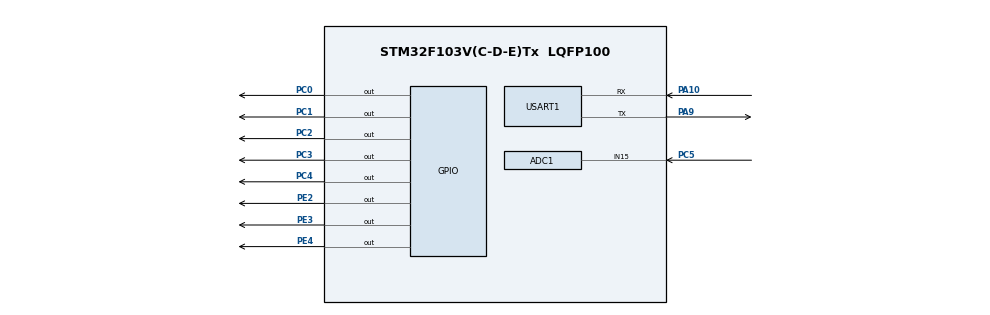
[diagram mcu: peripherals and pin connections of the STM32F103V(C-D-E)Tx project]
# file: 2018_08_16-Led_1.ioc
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ADC1.Channel-0\#ChannelRegularConversion=ADC_CHANNEL_15
ADC1.ContinuousConvMode=DISABLE
ADC1.DataAlign=ADC_DATAALIGN_RIGHT
ADC1.DiscontinuousConvMode=DISABLE
ADC1.EnableAnalogWatchDog=false
ADC1.EnableRegularConversion=ENABLE
ADC1.ExternalTrigConv=ADC_SOFTWARE_START
ADC1.InjNumberOfConversion=0
ADC1.NbrOfConversion=1
ADC1.NbrOfConversionFlag=1
ADC1.Rank-0\#ChannelRegularConversion=1
ADC1.SamplingTime-0\#ChannelRegularConversion=ADC_SAMPLETIME_1CYCLE_5
ADC1.ScanConvMode=ADC_SCAN_DISABLE
ADC1.master=1
Mcu.Family=STM32F1
Mcu.Name=STM32F103V(C-D-E)Tx
Mcu.Package=LQFP100
NVIC.PriorityGroup=NVIC_PRIORITYGROUP_4
OSC_IN.Mode=HSE-External-Oscillator
OSC_IN.Signal=RCC_OSC_IN
OSC_OUT.Mode=HSE-External-Oscillator
OSC_OUT.Signal=RCC_OSC_OUT
PA10.Mode=Asynchronous
PA10.Signal=USART1_RX
PA9.Mode=Asynchronous
PA9.Signal=USART1_TX
PC0.Signal=GPIO_Output
PC1.Signal=GPIO_Output
PC2.Signal=GPIO_Output
PC3.Signal=GPIO_Output
PC4.Signal=GPIO_Output
PC5.Signal=ADCx_IN15
PC6.Signal=S_TIM3_CH1
PE2.Signal=GPIO_Output
PE3.Signal=GPIO_Output
PE4.Signal=GPIO_Output
ProjectManager.HeapSize=0x200
ProjectManager.StackSize=0x400
ProjectManager.TargetToolchain=EWARM
RCC.ADCPresc=RCC_ADCPCLK2_DIV4
RCC.AHBFreq_Value=56000000
RCC.APB1CLKDivider=RCC_HCLK_DIV2
RCC.APB1Freq_Value=28000000
RCC.APB1TimFreq_Value=56000000
RCC.APB2Freq_Value=56000000
RCC.APB2TimFreq_Value=56000000
RCC.HCLKFreq_Value=56000000
RCC.PLLMUL=RCC_PLL_MUL7
RCC.PLLSourceVirtual=RCC_PLLSOURCE_HSE
RCC.SYSCLKFreq_VALUE=56000000
RCC.SYSCLKSource=RCC_SYSCLKSOURCE_PLLCLK
RCC.USBFreq_Value=56000000
SH.ADCx_IN15.0=ADC1_IN15,IN15
SH.S_TIM3_CH1.0=TIM3_CH1
USART1.VirtualMode=VM_ASYNC
VP_SYS_VS_ND.Mode=No_Debug
board=custom

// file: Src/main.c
/**
  ******************************************************************************
  * @file           : main.c
  * @brief          : Main program body
  ******************************************************************************
  ** This notice applies to any and all portions of this file
  * that are not between comment pairs USER CODE BEGIN and
  * USER CODE END. Other portions of this file, whether
  * inserted by the user or by software development tools
  * are owned by their respective copyright owners.
  *
  * COPYRIGHT(c) 2018 STMicroelectronics
  *
  * Redistribution and use in source and binary forms, with or without modification,
  * are permitted provided that the following conditions are met:
  *   1. Redistributions of source code must retain the above copyright notice,
  *      this list of conditions and the following disclaimer.
  *   2. Redistributions in binary form must reproduce the above copyright notice,
  *      this list of conditions and the following disclaimer in the documentation
  *      and/or other materials provided with the distribution.
  *   3. Neither the name of STMicroelectronics nor the names of its contributors
  *      may be used to endorse or promote products derived from this software
  *      without specific prior written permission.
  *
  * THIS SOFTWARE IS PROVIDED BY THE COPYRIGHT HOLDERS AND CONTRIBUTORS "AS IS"
  * AND ANY EXPRESS OR IMPLIED WARRANTIES, INCLUDING, BUT NOT LIMITED TO, THE
  * IMPLIED WARRANTIES OF MERCHANTABILITY AND FITNESS FOR A PARTICULAR PURPOSE ARE
  * DISCLAIMED. IN NO EVENT SHALL THE COPYRIGHT HOLDER OR CONTRIBUTORS BE LIABLE
  * FOR ANY DIRECT, INDIRECT, INCIDENTAL, SPECIAL, EXEMPLARY, OR CONSEQUENTIAL
  * DAMAGES (INCLUDING, BUT NOT LIMITED TO, PROCUREMENT OF SUBSTITUTE GOODS OR
  * SERVICES; LOSS OF USE, DATA, OR PROFITS; OR BUSINESS INTERRUPTION) HOWEVER
  * CAUSED AND ON ANY THEORY OF LIABILITY, WHETHER IN CONTRACT, STRICT LIABILITY,
  * OR TORT (INCLUDING NEGLIGENCE OR OTHERWISE) ARISING IN ANY WAY OUT OF THE USE
  * OF THIS SOFTWARE, EVEN IF ADVISED OF THE POSSIBILITY OF SUCH DAMAGE.
  *
  ******************************************************************************
  */
#include "main.h"
#include "stm32f1xx_hal.h"
#include "adc.h"
#include "usart.h"
#include "gpio.h"

/* USER CODE BEGIN PV */
/* Private variables ---------------------------------------------------------*/

/* USER CODE END PV */

void SystemClock_Config(void);

/* USER CODE BEGIN PFP */
/* Private function prototypes -----------------------------------------------*/

/* USER CODE END PFP */

int main(void)
{

  /* MCU Configuration----------------------------------------------------------*/

  /* Reset of all peripherals, Initializes the Flash interface and the Systick. */
  HAL_Init();

  /* Configure the system clock */
  SystemClock_Config();

  /* Initialize all configured peripherals */
  MX_GPIO_Init();
  MX_ADC1_Init();
  MX_USART1_UART_Init();

  /* Infinite loop */
  /* USER CODE BEGIN WHILE */
  while (1)
  {
    if(!(HAL_GPIO_ReadPin(GPIOC, GPIO_PIN_0)) )
    {
      HAL_GPIO_WritePin(GPIOE, GPIO_PIN_2|GPIO_PIN_3|GPIO_PIN_4, GPIO_PIN_SET);
    }
    else{
      HAL_GPIO_WritePin(GPIOE, GPIO_PIN_2|GPIO_PIN_3|GPIO_PIN_4, GPIO_PIN_RESET);
    }

  /* USER CODE END WHILE */

  }

}

void SystemClock_Config(void)
{

  RCC_OscInitTypeDef RCC_OscInitStruct;
  RCC_ClkInitTypeDef RCC_ClkInitStruct;
  RCC_PeriphCLKInitTypeDef PeriphClkInit;

    /**Initializes the CPU, AHB and APB busses clocks
    */
  RCC_OscInitStruct.OscillatorType = RCC_OSCILLATORTYPE_HSE;
  RCC_OscInitStruct.HSEState = RCC_HSE_ON;
  RCC_OscInitStruct.HSEPredivValue = RCC_HSE_PREDIV_DIV1;
  RCC_OscInitStruct.HSIState = RCC_HSI_ON;
  RCC_OscInitStruct.PLL.PLLState = RCC_PLL_ON;
  RCC_OscInitStruct.PLL.PLLSource = RCC_PLLSOURCE_HSE;
  RCC_OscInitStruct.PLL.PLLMUL = RCC_PLL_MUL9;
  if (HAL_RCC_OscConfig(&RCC_OscInitStruct) != HAL_OK)
  {
    _Error_Handler(__FILE__, __LINE__);
  }

    /**Initializes the CPU, AHB and APB busses clocks
    */
  RCC_ClkInitStruct.ClockType = RCC_CLOCKTYPE_HCLK|RCC_CLOCKTYPE_SYSCLK
                              |RCC_CLOCKTYPE_PCLK1|RCC_CLOCKTYPE_PCLK2;
  RCC_ClkInitStruct.SYSCLKSource = RCC_SYSCLKSOURCE_PLLCLK;
  RCC_ClkInitStruct.AHBCLKDivider = RCC_SYSCLK_DIV1;
  RCC_ClkInitStruct.APB1CLKDivider = RCC_HCLK_DIV2;
  RCC_ClkInitStruct.APB2CLKDivider = RCC_HCLK_DIV1;

  if (HAL_RCC_ClockConfig(&RCC_ClkInitStruct, FLASH_LATENCY_2) != HAL_OK)
  {
    _Error_Handler(__FILE__, __LINE__);
  }

  PeriphClkInit.PeriphClockSelection = RCC_PERIPHCLK_ADC;
  PeriphClkInit.AdcClockSelection = RCC_ADCPCLK2_DIV2;
  if (HAL_RCCEx_PeriphCLKConfig(&PeriphClkInit) != HAL_OK)
  {
    _Error_Handler(__FILE__, __LINE__);
  }

    /**Configure the Systick interrupt time
    */
  HAL_SYSTICK_Config(HAL_RCC_GetHCLKFreq()/1000);

    /**Configure the Systick
    */
  HAL_SYSTICK_CLKSourceConfig(SYSTICK_CLKSOURCE_HCLK);

  /* SysTick_IRQn interrupt configuration */
  HAL_NVIC_SetPriority(SysTick_IRQn, 0, 0);
}

void _Error_Handler(char *file, int line)
{
  while(1)
  {
  }
}

/************************ (C) COPYRIGHT STMicroelectronics *****END OF FILE****/
